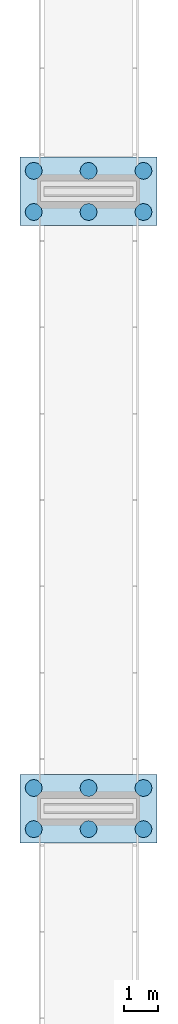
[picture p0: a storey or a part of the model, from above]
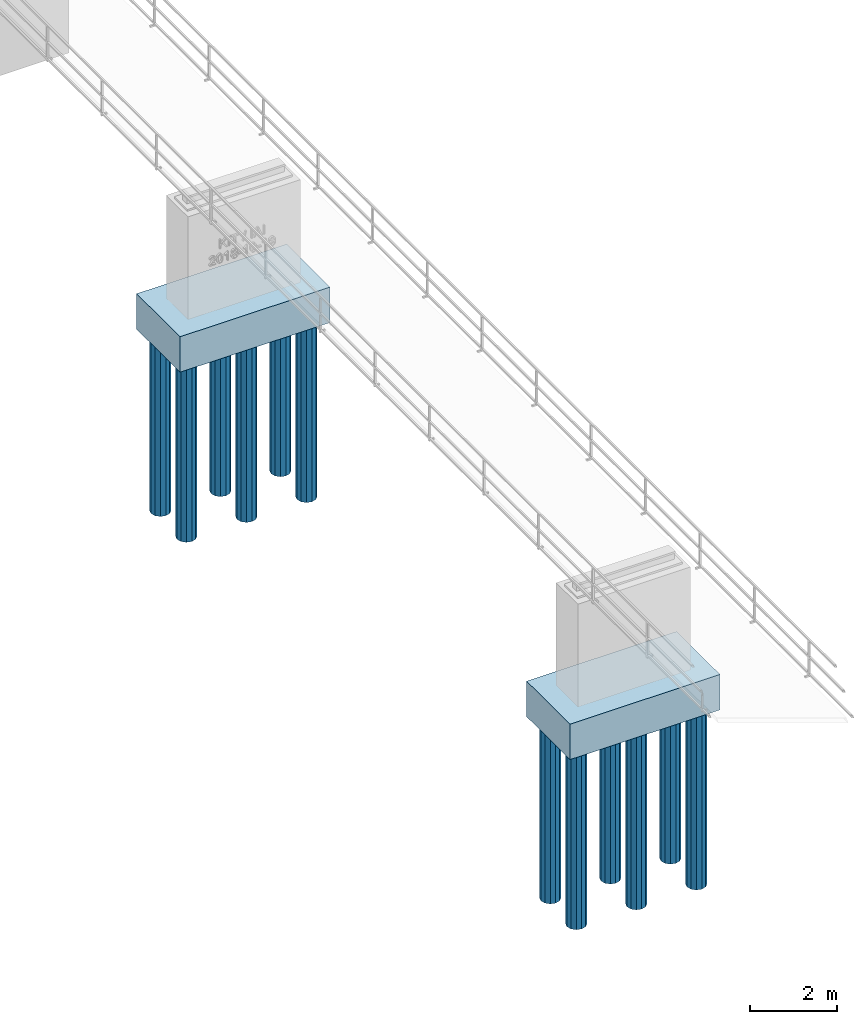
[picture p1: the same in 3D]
Properties of the parts of a building model (IFC4X2)

# File
Description: ViewDefinition [CoordinationView]
Time: 2018-10-30T17:42:13
Made in: SketchUp Pro 2015, manually edited by KHH at KIT/IAI

# IfcProject, Default Project
Description: Description of Default Project

# IfcSite, Default Site
Description: Description of Object; RefLatitude: 24, 28, 0; RefLongitude: 54, 25, 0; RefElevation: 10 mm
Generic - CompositionType: c

# IfcBearing (4)
Description: manually edited by KHH at KIT/IAI; PredefinedType: ELASTOMERIC
Name | In
2 x Bearing-02 | Substructure
Bearing-01 | Abutment 02
Bearing-04 | Abutment 01

# IfcBridge, KIT - Bridge
Description: Bridge manually edited by KHH at KIT/IAI

# IfcBridgePart (4)
Name | Description | PredefinedType
Superstructure | First attempt to model an IFC bridgePart Substructure manually edited by KHH at KIT/IAI | SUBSTRUCTURE
Substructure | Description of Default Building Storey | SUPERSTRUCTURE
Abutment 02 | manually edited by KHH at KIT/IAI | ABUTMENT
Abutment 01 | manually edited by KHH at KIT/IAI | ABUTMENT

# IfcColumn (2)
In: Substructure
Description: Description of Object; PredefinedType: PIERSTEM
Name
Column-01
Column-02

# IfcFooting (2)
In: Substructure
Description: Description of Object
PredefinedType - IfcFootingTypeEnum: footing_beam
Name
Foundation-02
Foundation-01

# IfcPile (12)
In: Substructure
Description: Description of Object; PredefinedType: BORED; ConstructionType: COMPOSITE
PredefinedType - IfcPileTypeEnum: cohesion
ConstructionType - IfcPileConstructionEnum: cast_in_place
Name
Pile-2-3
Pile-2-1
Pile-2-5
Pile-2-6
Pile-1-5
Pile-1-6
Pile-2-4
Pile-1-4
Pile-1-3
Pile-1-1
Pile-1-2
Pile-2-2

# IfcRailing (2)
In: Superstructure
Description: Description of Object
PredefinedType - IfcRailingTypeEnum: handrail
Name
Railing-01
Railing-02

# IfcSlab (3)
Description: Description of Object
PredefinedType - IfcSlabTypeEnum: floor
Name | In
Bridge-Slab-01 | Superstructure
 | Abutment 02
 | Abutment 01

# IfcVibrationDamper (4)
Description: manually edited by KHH at KIT/IAI; PredefinedType: VISCOUS
Name | In
Vibration Damper 02 (viscous) | Substructure
Vibration Damper 03 (viscous) | Substructure
Vibration Damper 01 (viscous) | Abutment 02
Vibration Damper 04 (viscous) | Abutment 01

# IfcVibrationIsolator (4)
Description: manually edited by KHH at KIT/IAI; PredefinedType: BASE
Name | In
Vibration Isolator 02 | Substructure
Vibration Isolator 03 | Substructure
Vibration Isolator 01 | Abutment 02
Vibration Isolator 04 | Abutment 01

# IfcWall (6)
Description: Description of Object; PredefinedType: RETAININGWALL
Name | In
3 x  | Abutment 02
3 x  | Abutment 01
